VERSION 5.7 ;
  NOWIREEXTENSIONATPIN ON ;
  DIVIDERCHAR "/" ;
  BUSBITCHARS "[]" ;
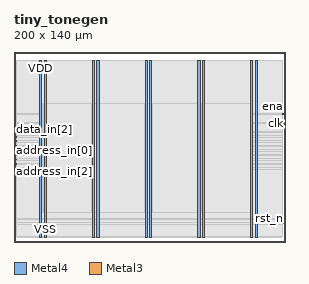
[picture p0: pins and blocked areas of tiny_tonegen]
MACRO tiny_tonegen
  CLASS BLOCK ;
  FOREIGN tiny_tonegen ;
  ORIGIN 0.000 0.000 ;
  SIZE 200.000 BY 140.000 ;
  PIN VDD
    DIRECTION INOUT ;
    USE POWER ;
    PORT
      LAYER Metal4 ;
        RECT 18.880 3.620 20.480 133.580 ;
    END
    PORT
      LAYER Metal4 ;
        RECT 57.750 3.620 59.350 133.580 ;
    END
    PORT
      LAYER Metal4 ;
        RECT 96.620 3.620 98.220 133.580 ;
    END
    PORT
      LAYER Metal4 ;
        RECT 135.490 3.620 137.090 133.580 ;
    END
    PORT
      LAYER Metal4 ;
        RECT 174.360 3.620 175.960 133.580 ;
    END
  END VDD
  PIN VSS
    DIRECTION INOUT ;
    USE GROUND ;
    PORT
      LAYER Metal4 ;
        RECT 22.180 3.620 23.780 133.580 ;
    END
    PORT
      LAYER Metal4 ;
        RECT 61.050 3.620 62.650 133.580 ;
    END
    PORT
      LAYER Metal4 ;
        RECT 99.920 3.620 101.520 133.580 ;
    END
    PORT
      LAYER Metal4 ;
        RECT 138.790 3.620 140.390 133.580 ;
    END
    PORT
      LAYER Metal4 ;
        RECT 177.660 3.620 179.260 133.580 ;
    END
  END VSS
  PIN address_in[0]
    DIRECTION INPUT ;
    USE SIGNAL ;
    ANTENNAGATEAREA 0.498500 ;
    PORT
      LAYER Metal3 ;
        RECT 0.000 67.200 2.000 67.760 ;
    END
  END address_in[0]
  PIN address_in[1]
    DIRECTION INPUT ;
    USE SIGNAL ;
    ANTENNAGATEAREA 1.102000 ;
    PORT
      LAYER Metal3 ;
        RECT 0.000 63.840 2.000 64.400 ;
    END
  END address_in[1]
  PIN address_in[2]
    DIRECTION INPUT ;
    USE SIGNAL ;
    ANTENNAGATEAREA 0.498500 ;
    PORT
      LAYER Metal3 ;
        RECT 0.000 57.120 2.000 57.680 ;
    END
  END address_in[2]
  PIN clk
    DIRECTION INPUT ;
    USE SIGNAL ;
    ANTENNAGATEAREA 4.738000 ;
    PORT
      LAYER Metal3 ;
        RECT 198.000 87.360 200.000 87.920 ;
    END
  END clk
  PIN data_in[0]
    DIRECTION INPUT ;
    USE SIGNAL ;
    ANTENNAGATEAREA 0.498500 ;
    PORT
      LAYER Metal3 ;
        RECT 0.000 53.760 2.000 54.320 ;
    END
  END data_in[0]
  PIN data_in[1]
    DIRECTION INPUT ;
    USE SIGNAL ;
    ANTENNAGATEAREA 0.498500 ;
    PORT
      LAYER Metal3 ;
        RECT 0.000 70.560 2.000 71.120 ;
    END
  END data_in[1]
  PIN data_in[2]
    DIRECTION INPUT ;
    USE SIGNAL ;
    ANTENNAGATEAREA 0.741000 ;
    PORT
      LAYER Metal3 ;
        RECT 0.000 77.280 2.000 77.840 ;
    END
  END data_in[2]
  PIN data_in[3]
    DIRECTION INPUT ;
    USE SIGNAL ;
    ANTENNAGATEAREA 0.741000 ;
    PORT
      LAYER Metal3 ;
        RECT 0.000 73.920 2.000 74.480 ;
    END
  END data_in[3]
  PIN data_in[4]
    DIRECTION INPUT ;
    USE SIGNAL ;
    ANTENNAGATEAREA 0.741000 ;
    PORT
      LAYER Metal3 ;
        RECT 0.000 80.640 2.000 81.200 ;
    END
  END data_in[4]
  PIN ena
    DIRECTION INPUT ;
    USE SIGNAL ;
    ANTENNAGATEAREA 0.741000 ;
    PORT
      LAYER Metal3 ;
        RECT 198.000 94.080 200.000 94.640 ;
    END
  END ena
  PIN rst_n
    DIRECTION INPUT ;
    USE SIGNAL ;
    ANTENNAGATEAREA 0.741000 ;
    PORT
      LAYER Metal3 ;
        RECT 198.000 16.800 200.000 17.360 ;
    END
  END rst_n
  PIN signal_bit_out
    DIRECTION OUTPUT ;
    USE SIGNAL ;
    ANTENNADIFFAREA 1.060800 ;
    PORT
      LAYER Metal3 ;
        RECT 198.000 13.440 200.000 14.000 ;
    END
  END signal_bit_out
  PIN write_strobe_in
    DIRECTION INPUT ;
    USE SIGNAL ;
    ANTENNAGATEAREA 0.741000 ;
    PORT
      LAYER Metal3 ;
        RECT 0.000 60.480 2.000 61.040 ;
    END
  END write_strobe_in
  OBS
      LAYER Nwell ;
        RECT 2.930 3.490 196.990 133.710 ;
      LAYER Metal1 ;
        RECT 3.360 3.620 196.560 133.580 ;
      LAYER Metal2 ;
        RECT 4.060 3.730 195.860 133.470 ;
      LAYER Metal3 ;
        RECT 2.000 94.940 198.000 133.420 ;
        RECT 2.000 93.780 197.700 94.940 ;
        RECT 2.000 88.220 198.000 93.780 ;
        RECT 2.000 87.060 197.700 88.220 ;
        RECT 2.000 81.500 198.000 87.060 ;
        RECT 2.300 80.340 198.000 81.500 ;
        RECT 2.000 78.140 198.000 80.340 ;
        RECT 2.300 76.980 198.000 78.140 ;
        RECT 2.000 74.780 198.000 76.980 ;
        RECT 2.300 73.620 198.000 74.780 ;
        RECT 2.000 71.420 198.000 73.620 ;
        RECT 2.300 70.260 198.000 71.420 ;
        RECT 2.000 68.060 198.000 70.260 ;
        RECT 2.300 66.900 198.000 68.060 ;
        RECT 2.000 64.700 198.000 66.900 ;
        RECT 2.300 63.540 198.000 64.700 ;
        RECT 2.000 61.340 198.000 63.540 ;
        RECT 2.300 60.180 198.000 61.340 ;
        RECT 2.000 57.980 198.000 60.180 ;
        RECT 2.300 56.820 198.000 57.980 ;
        RECT 2.000 54.620 198.000 56.820 ;
        RECT 2.300 53.460 198.000 54.620 ;
        RECT 2.000 17.660 198.000 53.460 ;
        RECT 2.000 16.500 197.700 17.660 ;
        RECT 2.000 14.300 198.000 16.500 ;
        RECT 2.000 13.140 197.700 14.300 ;
        RECT 2.000 3.780 198.000 13.140 ;
      LAYER Metal4 ;
        RECT 20.860 21.930 21.880 101.830 ;
        RECT 24.080 21.930 57.450 101.830 ;
        RECT 59.650 21.930 60.750 101.830 ;
        RECT 62.950 21.930 96.320 101.830 ;
        RECT 98.520 21.930 99.620 101.830 ;
        RECT 101.820 21.930 135.190 101.830 ;
        RECT 137.390 21.930 138.490 101.830 ;
        RECT 140.690 21.930 174.020 101.830 ;
  END
END tiny_tonegen
END LIBRARY

